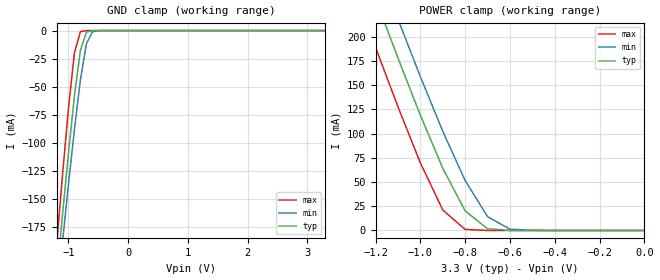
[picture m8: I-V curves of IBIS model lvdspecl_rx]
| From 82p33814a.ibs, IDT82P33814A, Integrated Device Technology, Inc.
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|   Model lvdspecl_rx
[Model]   lvdspecl_rx
Model_type   Input
Polarity   Non-Inverting
Enable   Active-High
C_comp   2.5000pF   2.4000pF   2.6000pF
Vinl=0.8V
Vinh=2.2V
[Temperature Range]   70.0000   0.1250k   0.0
[Voltage Range]   3.3000V   3.0000V   3.6000V
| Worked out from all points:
|   GND clamp passes 1 mA (typ) near -0.67 V on its own axis
|   POWER clamp passes 1 mA (typ) near -0.66 V on its own axis
[GND_clamp]
|Voltage   I(typ)   I(min)   I(max)
-3.3V     -1.503A    -1.423A    -1.63A
-1.2V     -221.6mA   -241.7mA   -192.5mA
-1.1V     -164.3mA   -188.7mA   -129mA
-1V       -109.2mA   -137.1mA   -69.1mA
-900mV    -58.13mA   -87.97mA   -19.68mA
-800mV    -17.58mA   -43.87mA   -879.5uA
-700mV    -1.429mA   -11.89mA   -13.27uA
-600mV    -52.38uA   -1.111mA   -190nA
-400mV    -60.87nA   -3.462uA   -69.74pA
3.3V      23.18pA    231.1nA    21pA
[POWER_clamp]
|Voltage   I(typ)   I(min)   I(max)
-3.3V     1.607A     1.634A     1.573A
-1.3V     301.4mA    340.8mA    251.9mA
-1.2V     239mA      278.8mA    188.9mA
-1.1V     177.9mA    218mA      127.6mA
-1V       118.9mA    158.7mA    69.7mA
-900mV    64.18mA    102.3mA    21.13mA
-800mV    20.16mA    51.46mA    1.068mA
-700mV    1.74mA     14.26mA    16.31uA
-600mV    64.41uA    1.362mA    233.7nA
-500mV    2.198uA    78.2uA     3.375nA
0V        23.18pA    51.1pA     25.2pA
